VERSION 5.7 ;
  NOWIREEXTENSIONATPIN ON ;
  DIVIDERCHAR "/" ;
  BUSBITCHARS "[]" ;
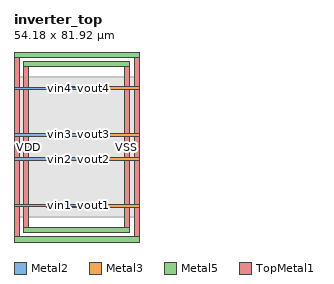
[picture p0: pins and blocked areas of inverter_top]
MACRO inverter_top
  CLASS BLOCK ;
  FOREIGN inverter_top ;
  ORIGIN 0.000 0.000 ;
  SIZE 54.180 BY 81.920 ;
  PIN vin1
    ANTENNAGATEAREA 140.000000 ;
    PORT
      LAYER Metal2 ;
        RECT 0.000 15.130 39.615 16.130 ;
    END
  END vin1
  PIN vin2
    ANTENNAGATEAREA 140.000000 ;
    PORT
      LAYER Metal2 ;
        RECT 0.000 35.230 39.615 36.230 ;
    END
  END vin2
  PIN vin3
    ANTENNAGATEAREA 140.000000 ;
    PORT
      LAYER Metal2 ;
        RECT 0.000 45.690 39.615 46.690 ;
    END
  END vin3
  PIN vin4
    ANTENNAGATEAREA 140.000000 ;
    PORT
      LAYER Metal2 ;
        RECT 0.000 65.790 39.615 66.790 ;
    END
  END vin4
  PIN vout1
    ANTENNADIFFAREA 26.599998 ;
    PORT
      LAYER Metal3 ;
        RECT 14.170 14.880 54.180 16.380 ;
    END
  END vout1
  PIN vout2
    ANTENNADIFFAREA 26.599998 ;
    PORT
      LAYER Metal3 ;
        RECT 14.170 34.980 54.180 36.480 ;
    END
  END vout2
  PIN vout3
    ANTENNADIFFAREA 26.599998 ;
    PORT
      LAYER Metal3 ;
        RECT 14.170 45.440 54.180 46.940 ;
    END
  END vout3
  PIN vout4
    ANTENNADIFFAREA 26.599998 ;
    PORT
      LAYER Metal3 ;
        RECT 14.170 65.540 54.180 67.040 ;
    END
  END vout4
  PIN VSS
    USE GROUND ;
    PORT
      LAYER Metal5 ;
        RECT 0.000 0.000 54.180 2.200 ;
    END
    PORT
      LAYER Metal5 ;
        RECT 0.000 79.720 54.180 81.920 ;
    END
    PORT
      LAYER TopMetal1 ;
        RECT 0.000 0.000 2.200 81.920 ;
    END
    PORT
      LAYER TopMetal1 ;
        RECT 51.980 0.000 54.180 81.920 ;
    END
  END VSS
  PIN VDD
    USE POWER ;
    PORT
      LAYER Metal5 ;
        RECT 4.200 4.200 49.980 6.400 ;
    END
    PORT
      LAYER Metal5 ;
        RECT 4.200 75.520 49.980 77.720 ;
    END
    PORT
      LAYER TopMetal1 ;
        RECT 47.780 4.200 49.980 77.720 ;
    END
    PORT
      LAYER TopMetal1 ;
        RECT 4.200 4.200 6.400 77.720 ;
    END
  END VDD
  OBS
      LAYER GatPoly ;
        RECT 10.750 11.900 43.430 70.020 ;
      LAYER Metal1 ;
        RECT 10.750 10.400 43.430 71.520 ;
      LAYER Metal2 ;
        RECT 10.750 67.000 43.430 71.520 ;
        RECT 39.825 65.580 43.430 67.000 ;
        RECT 10.750 46.900 43.430 65.580 ;
        RECT 39.825 45.480 43.430 46.900 ;
        RECT 10.750 36.440 43.430 45.480 ;
        RECT 39.825 35.020 43.430 36.440 ;
        RECT 10.750 16.340 43.430 35.020 ;
        RECT 39.825 14.920 43.430 16.340 ;
        RECT 10.750 10.400 43.430 14.920 ;
      LAYER Metal3 ;
        RECT 0.000 67.250 54.180 71.520 ;
        RECT 0.000 65.330 13.960 67.250 ;
        RECT 0.000 47.150 54.180 65.330 ;
        RECT 0.000 45.230 13.960 47.150 ;
        RECT 0.000 36.690 54.180 45.230 ;
        RECT 0.000 34.770 13.960 36.690 ;
        RECT 0.000 16.590 54.180 34.770 ;
        RECT 0.000 14.670 13.960 16.590 ;
        RECT 0.000 10.400 54.180 14.670 ;
      LAYER Metal4 ;
        RECT 0.750 10.845 53.430 71.075 ;
      LAYER Metal5 ;
        RECT 0.750 10.840 53.430 71.080 ;
  END
END inverter_top
END LIBRARY

